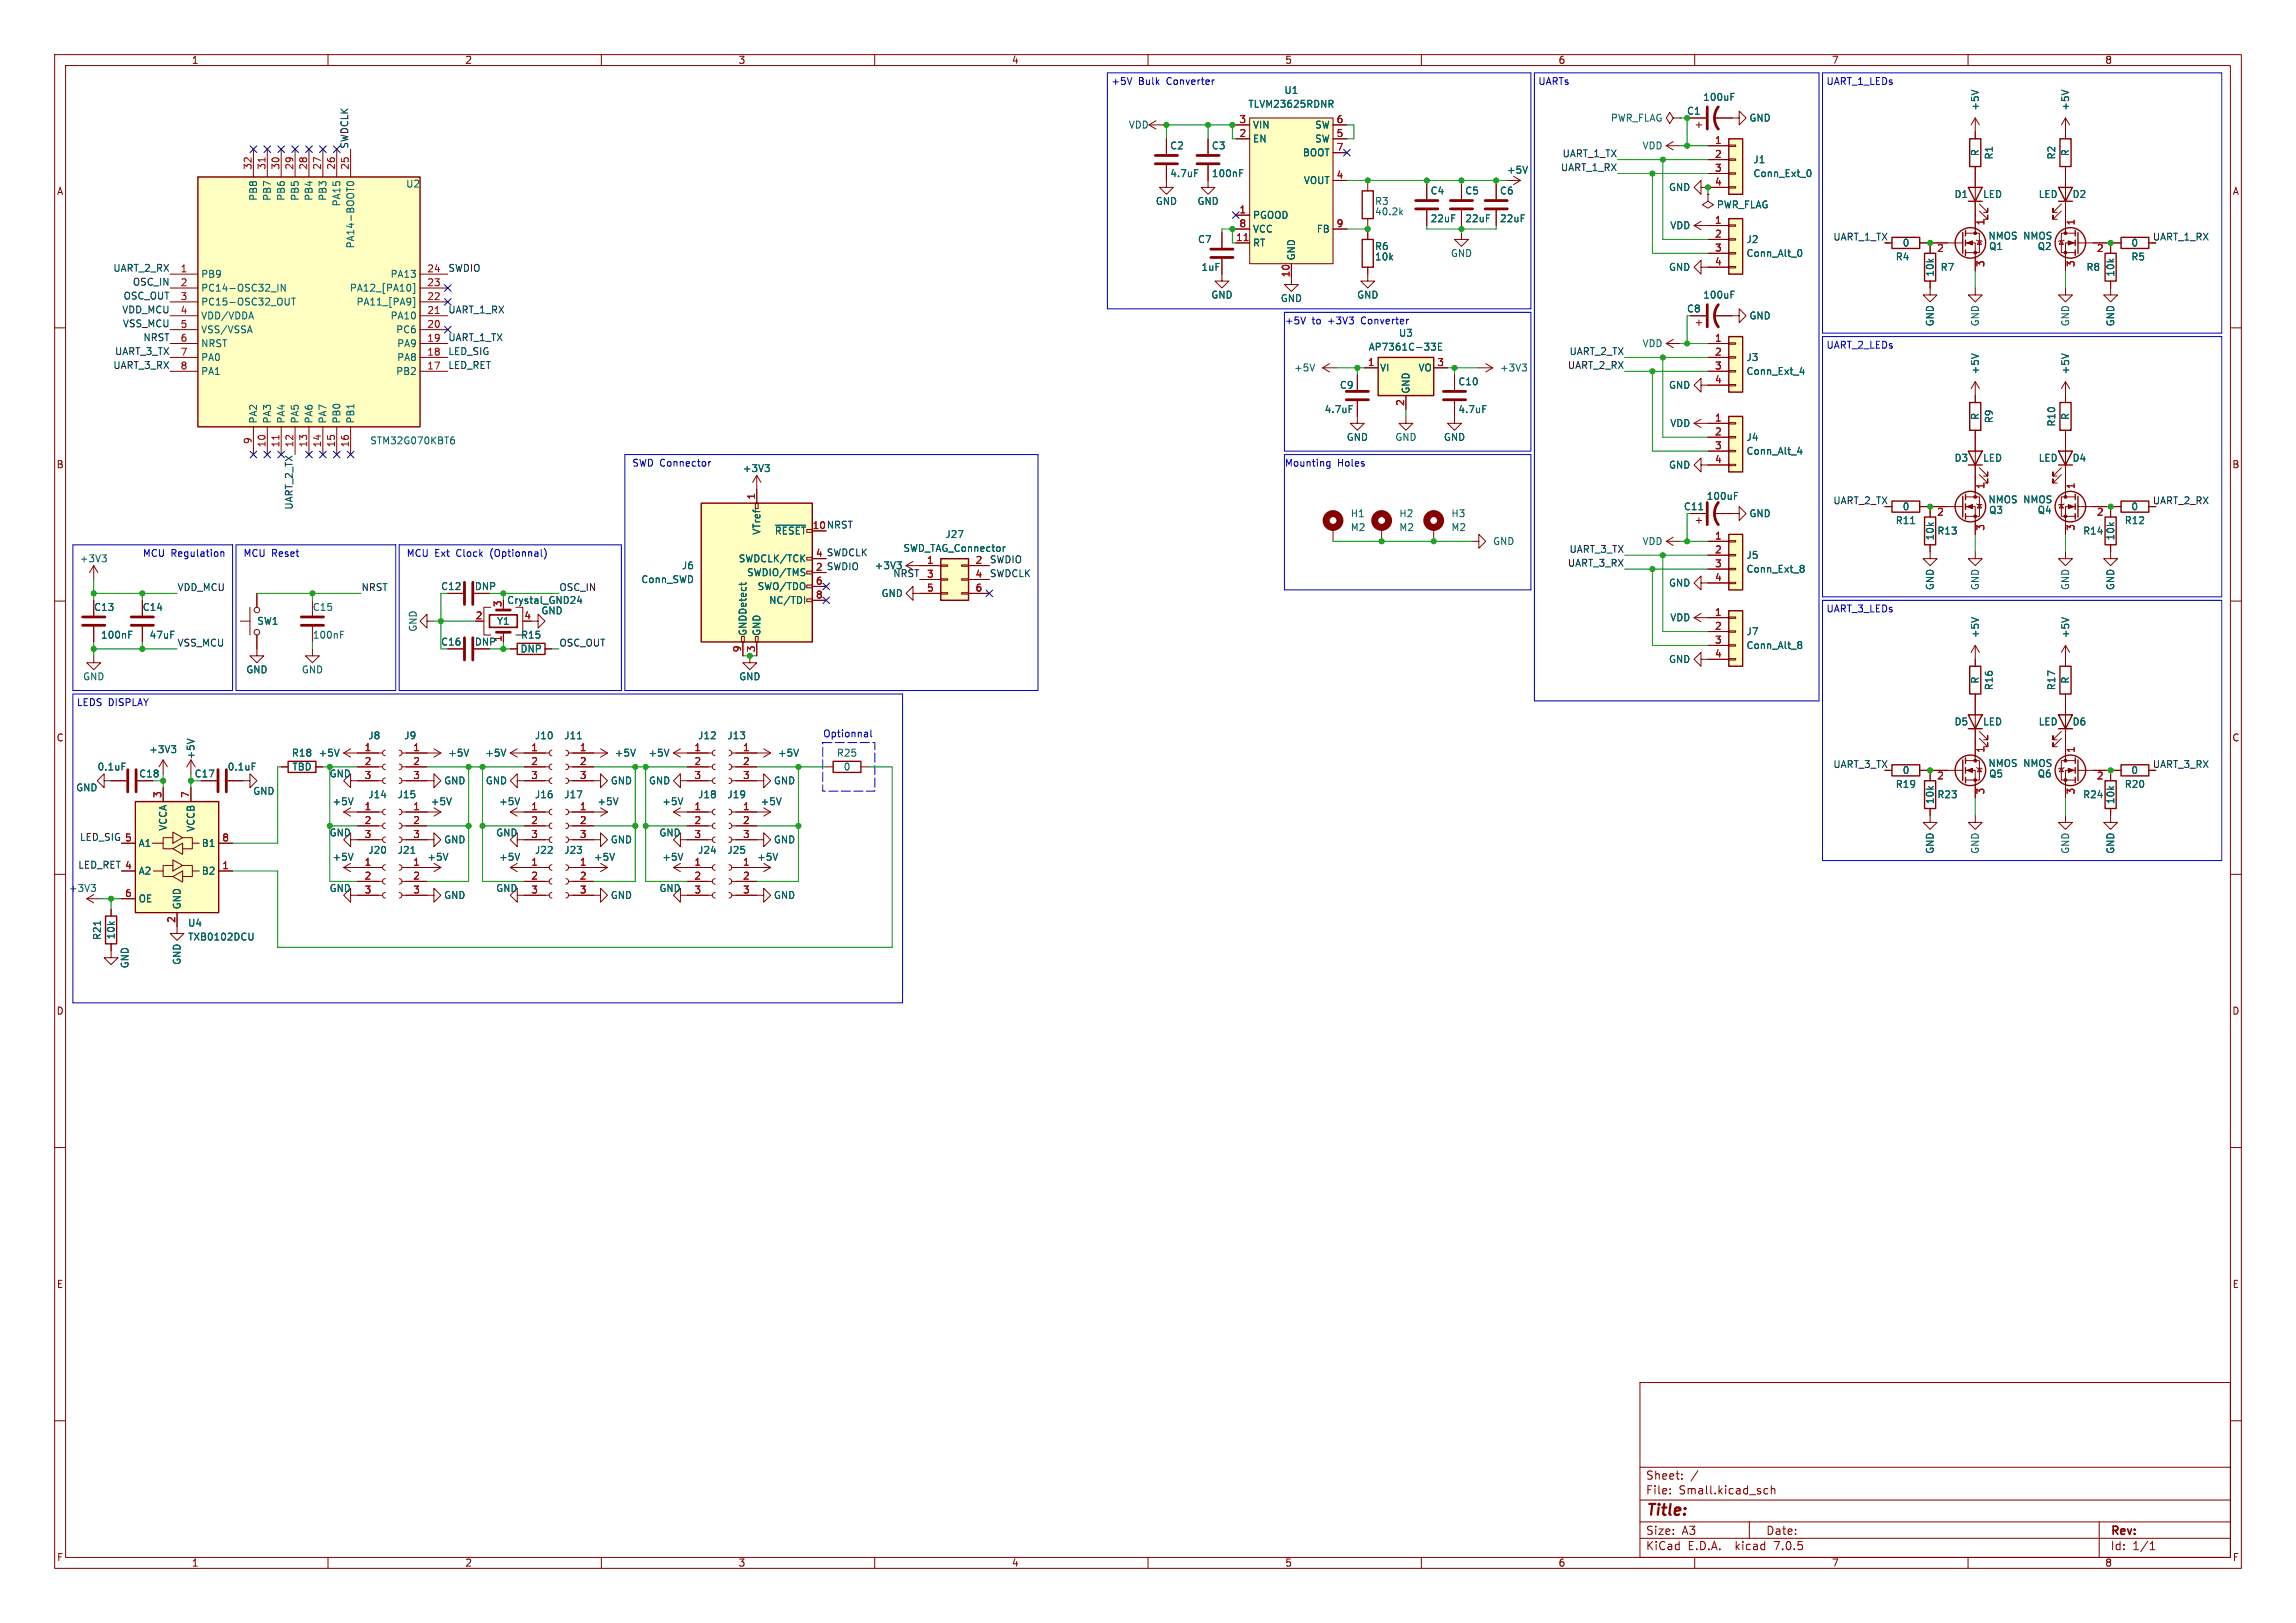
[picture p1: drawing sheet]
<svg xmlns="http://www.w3.org/2000/svg" width="420mm" height="297mm" viewBox="0 0 420 297" stroke-linecap="round" stroke-linejoin="round" font-family="sans-serif">
<defs><g id="words">
<text font-size="2.8" fill="#840000" x="301" y="277.8">Title:</text>
<g font-size="2.1" fill="#840000">
<text x="301" y="273.6">File:</text>
<text x="301" y="270.9">Sheet:</text>
<text x="307" y="273.6">Small.kicad_sch</text>
<text x="301" y="281">Size:</text>
<text x="307.6" y="281">A3</text>
<text x="323" y="281">Date:</text>
<text x="386" y="281.2">Rev:</text>
<text x="301" y="283.8">KiCad</text>
<text x="308.6" y="283.8">E.D.A.</text>
<text x="317.4" y="283.8">kicad</text>
<text x="324.5" y="283.8">7.0.5</text>
<text x="386" y="283.8">Id:</text>
<text x="390" y="283.8">1/1</text>
</g>
<g font-size="1.8" fill="#840000">
<text x="35" y="11.8">1</text>
<text x="85" y="11.8">2</text>
<text x="135" y="11.8">3</text>
<text x="185" y="11.8">4</text>
<text x="235" y="11.8">5</text>
<text x="285" y="11.8">6</text>
<text x="335" y="11.8">7</text>
<text x="385" y="11.8">8</text>
<text x="10.4" y="35.8">A</text>
<text x="408.4" y="35.8">A</text>
<text x="10.3" y="85.8">B</text>
<text x="408.3" y="85.8">B</text>
<text x="148.6" y="96.9">10 NRST</text>
<text x="86.8" y="108.1">DNP</text>
<text x="86.8" y="118.3">DNP</text>
<text x="10.3" y="135.8">C</text>
<text x="408.3" y="135.8">C</text>
<text x="25.4" y="142.4">C18</text>
<text x="10.3" y="185.8">D</text>
<text x="408.3" y="185.8">D</text>
<text x="10.4" y="235.8">E</text>
<text x="408.3" y="235.8">E</text>
<text x="10.4" y="285.8">F</text>
<text x="35" y="286.8">1</text>
<text x="85" y="286.8">2</text>
<text x="135" y="286.8">3</text>
<text x="185" y="286.8">4</text>
<text x="235" y="286.8">5</text>
<text x="285" y="286.8">6</text>
<text x="335" y="286.8">7</text>
<text x="385" y="286.8">8</text>
<text x="408.4" y="285.8">F</text>
</g>
<g font-size="1.8" fill="#0000c2">
<text x="203.2" y="15.6">+5V</text>
<text x="208.2" y="15.6">Bulk</text>
<text x="213.4" y="15.6">Converter</text>
<text x="281.3" y="15.6">UARTs</text>
<text x="334" y="15.6">UART_1_LEDs</text>
<text x="234.9" y="59.4">+5V</text>
<text x="239.9" y="59.4">to</text>
<text x="242.9" y="59.4">+3V3</text>
<text x="249.1" y="59.4">Converter</text>
<text x="334" y="63.9">UART_2_LEDs</text>
<text x="115.6" y="85.5">SWD Connector</text>
<text x="234.9" y="85.5">Mounting</text>
<text x="244.6" y="85.5">Holes</text>
<text x="26" y="102">MCU Regulation</text>
<text x="44.4" y="102">MCU Reset</text>
<text x="74.3" y="102">MCU Ext</text>
<text x="83.4" y="102">Clock</text>
<text x="89.7" y="102">(Optionnal)</text>
<text x="334" y="112.1">UART_3_LEDs</text>
<text x="14" y="129.3">LEDS DISPLAY</text>
<text x="150.5" y="135">Optionnal</text>
</g>
<g font-size="1.8" fill="#006464">
<text x="234.9" y="17.3">U1</text>
<text x="206.4" y="23.7">VDD</text>
<text x="228.3" y="19.9">TLVM23625RDNR</text>
<text x="229.1" y="23.7">VIN</text>
<text x="240.5" y="23.7">SW</text>
<text x="294.6" y="22.4">PWR_FLAG</text>
<text x="308.5" y="21.1">C1</text>
<text x="311.5" y="18.6">100uF</text>
<text x="319.9" y="22.4">GND</text>
<text x="362.1" y="20.3" transform="rotate(-90 362.1 20.3)">+5V</text>
<text x="378.7" y="20.3" transform="rotate(-90 378.7 20.3)">+5V</text>
<text x="214" y="27.5">C2</text>
<text x="221.6" y="27.5">C3</text>
<text x="229.1" y="26.2">EN</text>
<text x="238.3" y="28.8">BOOT</text>
<text x="240.5" y="26.2">SW</text>
<text x="300.4" y="27.5">VDD</text>
<text x="362.1" y="28.6" transform="rotate(-90 362.1 28.6)">R</text>
<text x="364.7" y="29.2" transform="rotate(-90 364.7 29.2)">R1</text>
<text x="376.1" y="29.2" transform="rotate(-90 376.1 29.2)">R2</text>
<text x="378.7" y="28.6" transform="rotate(-90 378.7 28.6)">R</text>
<text x="74.2" y="34.5">U2</text>
<text x="214" y="32.6">4.7uF</text>
<text x="221.6" y="32.6">100nF</text>
<text x="238.5" y="33.8">VOUT</text>
<text x="261.6" y="35.8">C4</text>
<text x="268" y="35.8">C5</text>
<text x="274.3" y="35.8">C6</text>
<text x="275.6" y="31.9">+5V</text>
<text x="305.2" y="35.1">GND</text>
<text x="320.7" y="30">J1</text>
<text x="320.7" y="32.6">Conn_Ext_0</text>
<text x="47.2" y="36.8" transform="rotate(-90 47.2 36.8)">PB8</text>
<text x="49.7" y="36.8" transform="rotate(-90 49.7 36.8)">PB7</text>
<text x="52.3" y="36.8" transform="rotate(-90 52.3 36.8)">PB6</text>
<text x="54.8" y="36.8" transform="rotate(-90 54.8 36.8)">PB5</text>
<text x="57.3" y="36.8" transform="rotate(-90 57.3 36.8)">PB4</text>
<text x="59.9" y="36.8" transform="rotate(-90 59.9 36.8)">PB3</text>
<text x="62.4" y="37.8" transform="rotate(-90 62.4 37.8)">PA15</text>
<text x="211.4" y="37.7">GND</text>
<text x="219" y="37.7">GND</text>
<text x="229.1" y="40.2">PGOOD</text>
<text x="251.5" y="37.7">R3</text>
<text x="251.5" y="39.6">40.2k</text>
<text x="261.6" y="40.8">22uF</text>
<text x="268" y="40.8">22uF</text>
<text x="274.3" y="40.8">22uF</text>
<text x="314" y="38.3">PWR_FLAG</text>
<text x="357.5" y="36.4">D1</text>
<text x="362.7" y="36.4">LED</text>
<text x="372.9" y="36.4">LED</text>
<text x="379.1" y="36.4">D2</text>
<text x="65" y="45.5" transform="rotate(-90 65 45.5)">PA14-BOOT0</text>
<text x="219.1" y="44.6">C7</text>
<text x="229.1" y="45.3">RT</text>
<text x="229.1" y="42.7">VCC</text>
<text x="237" y="47.8" transform="rotate(-90 237 47.8)">GND</text>
<text x="240.8" y="42.7">FB</text>
<text x="251.5" y="45.9">R6</text>
<text x="251.5" y="47.8">10k</text>
<text x="265.3" y="47.2">GND</text>
<text x="305.5" y="42.1">VDD</text>
<text x="319.4" y="44.6">J2</text>
<text x="319.4" y="47.2">Conn_Alt_0</text>
<text x="346.7" y="47.8">R4</text>
<text x="348" y="45.3">0</text>
<text x="363.7" y="44">NMOS NMOS</text>
<text x="363.8" y="45.9">Q1</text>
<text x="372.7" y="45.9">Q2</text>
<text x="389.8" y="47.8">R5</text>
<text x="389.8" y="45.3">0</text>
<text x="36.7" y="51">PB9</text>
<text x="36.7" y="53.5">PC14-OSC32_IN</text>
<text x="64" y="53.5">PA12_[PA10]</text>
<text x="71.4" y="51">PA13</text>
<text x="219.7" y="49.7">1uF</text>
<text x="305.2" y="49.7">GND</text>
<text x="353.9" y="50.7" transform="rotate(-90 353.9 50.7)">10k</text>
<text x="354.9" y="49.7">R7</text>
<text x="381.6" y="49.7">R8</text>
<text x="386.9" y="50.7" transform="rotate(-90 386.9 50.7)">10k</text>
<text x="36.7" y="56.1">PC15-OSC32_OUT</text>
<text x="36.7" y="58.6">VDD/VDDA</text>
<text x="65.2" y="56.1">PA11_[PA9]</text>
<text x="71.4" y="58.6">PA10</text>
<text x="221.5" y="54.8">GND</text>
<text x="234.2" y="55.4">GND</text>
<text x="248.2" y="54.8">GND</text>
<text x="308.5" y="57.3">C8</text>
<text x="311.5" y="54.8">100uF</text>
<text x="319.9" y="58.6">GND</text>
<text x="353.9" y="59.8" transform="rotate(-90 353.9 59.8)">GND</text>
<text x="362.1" y="59.8" transform="rotate(-90 362.1 59.8)">GND</text>
<text x="378.7" y="59.8" transform="rotate(-90 378.7 59.8)">GND</text>
<text x="386.9" y="59.8" transform="rotate(-90 386.9 59.8)">GND</text>
<text x="36.7" y="61.2">VSS/VSSA</text>
<text x="36.7" y="63.7">NRST</text>
<text x="72.5" y="61.2">PC6</text>
<text x="72.6" y="63.7">PA9</text>
<text x="250.3" y="64.3">AP7361C-33E</text>
<text x="255.8" y="61.8">U3</text>
<text x="300.4" y="63.7">VDD</text>
<text x="36.7" y="66.2">PA0</text>
<text x="36.7" y="68.8">PA1</text>
<text x="72.5" y="68.8">PB2</text>
<text x="72.6" y="66.2">PA8</text>
<text x="236.7" y="68.1">+5V</text>
<text x="245" y="71.3">C9</text>
<text x="252.3" y="68.1">VI</text>
<text x="259.5" y="68.1">VO</text>
<text x="266.7" y="70.7">C10</text>
<text x="274.3" y="68.1">+3V3</text>
<text x="305.2" y="71.3">GND</text>
<text x="319.4" y="66.2">J3</text>
<text x="319.4" y="68.8">Conn_Ext_4</text>
<text x="362.1" y="68.6" transform="rotate(-90 362.1 68.6)">+5V</text>
<text x="378.7" y="68.6" transform="rotate(-90 378.7 68.6)">+5V</text>
<text x="47.2" y="77.6" transform="rotate(-90 47.2 77.6)">PA2</text>
<text x="49.7" y="77.6" transform="rotate(-90 49.7 77.6)">PA3</text>
<text x="52.3" y="77.6" transform="rotate(-90 52.3 77.6)">PA4</text>
<text x="54.8" y="77.6" transform="rotate(-90 54.8 77.6)">PA5</text>
<text x="57.3" y="77.6" transform="rotate(-90 57.3 77.6)">PA6</text>
<text x="59.9" y="77.6" transform="rotate(-90 59.9 77.6)">PA7</text>
<text x="62.4" y="77.6" transform="rotate(-90 62.4 77.6)">PB0</text>
<text x="65" y="77.6" transform="rotate(-90 65 77.6)">PB1</text>
<text x="242.3" y="75.8">4.7uF</text>
<text x="258" y="72.1" transform="rotate(-90 258 72.1)">GND</text>
<text x="266.7" y="75.8">4.7uF</text>
<text x="362.1" y="76.9" transform="rotate(-90 362.1 76.9)">R</text>
<text x="364.7" y="77.5" transform="rotate(-90 364.7 77.5)">R9</text>
<text x="378.7" y="76.9" transform="rotate(-90 378.7 76.9)">R</text>
<text x="67.7" y="81.5">STM32G070KBT6</text>
<text x="246.3" y="80.8">GND</text>
<text x="255.2" y="80.8">GND</text>
<text x="264.1" y="80.8">GND</text>
<text x="305.5" y="78.3">VDD</text>
<text x="319.4" y="80.8">J4</text>
<text x="319.4" y="83.4">Conn_Alt_4</text>
<text x="376.1" y="78.1" transform="rotate(-90 376.1 78.1)">R10</text>
<text x="135.8" y="86.6">+3V3</text>
<text x="305.2" y="85.9">GND</text>
<text x="357.5" y="84.6">D3</text>
<text x="362.7" y="84.6">LED</text>
<text x="372.9" y="84.6">LED</text>
<text x="379.1" y="84.6">D4</text>
<text x="247" y="94.8">H1</text>
<text x="255.9" y="94.8">H2</text>
<text x="265.4" y="94.8">H3</text>
<text x="308" y="93.5">C11</text>
<text x="312.1" y="91.6">100uF</text>
<text x="319.9" y="94.8">GND</text>
<text x="348" y="93.5">0</text>
<text x="363.7" y="92.3">NMOS NMOS</text>
<text x="363.8" y="94.2">Q3</text>
<text x="372.7" y="94.2">Q4</text>
<text x="389.8" y="93.5">0</text>
<text x="139.3" y="97.9" transform="rotate(-90 139.3 97.9)">VTref</text>
<text x="141.7" y="98">~{RESET}</text>
<text x="165.2" y="101.2">SWD_TAG_Connector</text>
<text x="172.9" y="98.6">J27</text>
<text x="247" y="97.3">M2</text>
<text x="255.9" y="97.3">M2</text>
<text x="265.4" y="97.3">M2</text>
<text x="273.1" y="99.9">GND</text>
<text x="300.4" y="99.9">VDD</text>
<text x="346.7" y="96.1">R11</text>
<text x="353.9" y="98.9" transform="rotate(-90 353.9 98.9)">10k</text>
<text x="354.3" y="98">R13</text>
<text x="381" y="98">R14</text>
<text x="386.9" y="98.9" transform="rotate(-90 386.9 98.9)">10k</text>
<text x="388.6" y="96.1">R12</text>
<text x="14.5" y="103.1">+3V3</text>
<text x="117.2" y="106.9">Conn_SWD</text>
<text x="124.7" y="104.3">J6</text>
<text x="135.1" y="103.1">SWDCLK/TCK</text>
<text x="136.6" y="105.6">SWDIO/TMS</text>
<text x="160" y="104.3">+3V3</text>
<text x="163.4" y="105.7">NRST</text>
<text x="305.2" y="107.5">GND</text>
<text x="319.4" y="102.4">J5</text>
<text x="319.4" y="105">Conn_Ext_8</text>
<text x="17.2" y="112">C13</text>
<text x="26" y="112">C14</text>
<text x="57.2" y="112">C15</text>
<text x="80.6" y="108.1">C12</text>
<text x="92.7" y="110.7">Crystal_GND24</text>
<text x="99" y="112.6">GND</text>
<text x="138.6" y="108.1">SWO/TDO</text>
<text x="140.7" y="110.7">NC/TDI</text>
<text x="161.2" y="109.4">GND</text>
<text x="305.5" y="113.9">VDD</text>
<text x="353.9" y="108" transform="rotate(-90 353.9 108)">GND</text>
<text x="362.1" y="108" transform="rotate(-90 362.1 108)">GND</text>
<text x="378.7" y="108" transform="rotate(-90 378.7 108)">GND</text>
<text x="386.9" y="108" transform="rotate(-90 386.9 108)">GND</text>
<text x="18.4" y="117">100nF</text>
<text x="27.3" y="117">47uF</text>
<text x="47" y="114.5">SW1</text>
<text x="57.2" y="117">100nF</text>
<text x="76.4" y="115.7" transform="rotate(-90 76.4 115.7)">GND</text>
<text x="80.6" y="118.3">C16</text>
<text x="90.9" y="114.5">Y1</text>
<text x="91.8" y="117.5" transform="rotate(-90 91.8 117.5)">1</text>
<text x="95.2" y="119.6">DNP</text>
<text x="95.2" y="117">R15</text>
<text x="136.7" y="116.5" transform="rotate(-90 136.7 116.5)">GNDDetect</text>
<text x="139.3" y="116.5" transform="rotate(-90 139.3 116.5)">GND</text>
<text x="319.4" y="116.4">J7</text>
<text x="319.4" y="118.9">Conn_Alt_8</text>
<text x="362.1" y="116.8" transform="rotate(-90 362.1 116.8)">+5V</text>
<text x="378.7" y="116.8" transform="rotate(-90 378.7 116.8)">+5V</text>
<text x="15.1" y="124.7">GND</text>
<text x="45" y="123.4">GND</text>
<text x="55.2" y="123.4">GND</text>
<text x="135.2" y="124.7">GND</text>
<text x="305.2" y="121.5">GND</text>
<text x="362.1" y="125.2" transform="rotate(-90 362.1 125.2)">R</text>
<text x="378.7" y="125.2" transform="rotate(-90 378.7 125.2)">R</text>
<text x="364.7" y="126.4" transform="rotate(-90 364.7 126.4)">R16</text>
<text x="376.1" y="126.4" transform="rotate(-90 376.1 126.4)">R17</text>
<text x="27.2" y="138">+3V3</text>
<text x="67.3" y="135.4">J8</text>
<text x="73.9" y="135.4">J9</text>
<text x="97.8" y="135.4">J10</text>
<text x="103.2" y="135.4">J11</text>
<text x="127.6" y="135.4">J12</text>
<text x="133" y="135.4">J13</text>
<text x="357.5" y="132.9">D5</text>
<text x="362.7" y="132.9">LED</text>
<text x="372.9" y="132.9">LED</text>
<text x="379.1" y="132.9">D6</text>
<text x="17.8" y="141.2">0.1uF</text>
<text x="35.5" y="142.4">C17</text>
<text x="35.8" y="139.1" transform="rotate(-90 35.8 139.1)">+5V</text>
<text x="41.6" y="141.2">0.1uF</text>
<text x="53.3" y="138.6">R18</text>
<text x="53.4" y="141.2">TBD</text>
<text x="58.2" y="138.6">+5V</text>
<text x="60.2" y="142.4">GND</text>
<text x="81.2" y="143.7">GND</text>
<text x="81.9" y="138.6">+5V</text>
<text x="88.7" y="138.6">+5V</text>
<text x="88.8" y="143.7">GND</text>
<text x="111.7" y="143.7">GND</text>
<text x="112.4" y="138.6">+5V</text>
<text x="118.5" y="138.6">+5V</text>
<text x="118.7" y="143.7">GND</text>
<text x="141.5" y="143.7">GND</text>
<text x="142.2" y="138.6">+5V</text>
<text x="153" y="138.6">R25</text>
<text x="154.3" y="141.2">0</text>
<text x="348" y="141.8">0</text>
<text x="363.7" y="140.5">NMOS NMOS</text>
<text x="363.8" y="142.4">Q5</text>
<text x="372.7" y="142.4">Q6</text>
<text x="389.8" y="141.8">0</text>
<text x="13.9" y="145">GND</text>
<text x="46.3" y="145.6">GND</text>
<text x="60.8" y="147.5">+5V</text>
<text x="67.3" y="146.2">J14</text>
<text x="72.7" y="146.2">J15</text>
<text x="78.7" y="147.5">+5V</text>
<text x="91.2" y="147.5">+5V</text>
<text x="97.8" y="146.2">J16</text>
<text x="103.2" y="146.2">J17</text>
<text x="109.2" y="147.5">+5V</text>
<text x="121.1" y="147.5">+5V</text>
<text x="127.6" y="146.2">J18</text>
<text x="133" y="146.2">J19</text>
<text x="139.1" y="147.5">+5V</text>
<text x="346.7" y="144.3">R19</text>
<text x="353.9" y="147.2" transform="rotate(-90 353.9 147.2)">10k</text>
<text x="354.3" y="146.2">R23</text>
<text x="381" y="146.2">R24</text>
<text x="386.9" y="147.2" transform="rotate(-90 386.9 147.2)">10k</text>
<text x="388.6" y="144.3">R20</text>
<text x="25.3" y="155.1">A1</text>
<text x="30.7" y="152" transform="rotate(-90 30.7 152)">VCCA</text>
<text x="35.8" y="152.2" transform="rotate(-90 35.8 152.2)">VCCB</text>
<text x="36.9" y="155.1">B1</text>
<text x="60.2" y="153.2">GND</text>
<text x="81.2" y="154.5">GND</text>
<text x="90.7" y="153.2">GND</text>
<text x="111.7" y="154.5">GND</text>
<text x="120.6" y="153.2">GND</text>
<text x="141.5" y="154.5">GND</text>
<text x="25.3" y="160.2">A2</text>
<text x="36.9" y="160.2">B2</text>
<text x="60.8" y="157.7">+5V</text>
<text x="67.3" y="156.4">J20</text>
<text x="72.7" y="156.4">J21</text>
<text x="78.1" y="157.7">+5V</text>
<text x="91.2" y="157.7">+5V</text>
<text x="97.8" y="156.4">J22</text>
<text x="103.2" y="156.4">J23</text>
<text x="108.6" y="157.7">+5V</text>
<text x="121.1" y="157.7">+5V</text>
<text x="127.6" y="156.4">J24</text>
<text x="133" y="156.4">J25</text>
<text x="138.4" y="157.7">+5V</text>
<text x="353.9" y="156.3" transform="rotate(-90 353.9 156.3)">GND</text>
<text x="362.1" y="156.3" transform="rotate(-90 362.1 156.3)">GND</text>
<text x="378.7" y="156.3" transform="rotate(-90 378.7 156.3)">GND</text>
<text x="386.9" y="156.3" transform="rotate(-90 386.9 156.3)">GND</text>
<text x="12.6" y="163.4">+3V3</text>
<text x="25.3" y="165.3">OE</text>
<text x="33.2" y="166.5" transform="rotate(-90 33.2 166.5)">GND</text>
<text x="60.2" y="163.4">GND</text>
<text x="81.2" y="164.7">GND</text>
<text x="90.7" y="163.4">GND</text>
<text x="111.7" y="164.7">GND</text>
<text x="120.6" y="163.4">GND</text>
<text x="141.5" y="164.7">GND</text>
<text x="18.6" y="172.1" transform="rotate(-90 18.6 172.1)">R21</text>
<text x="21.1" y="172" transform="rotate(-90 21.1 172)">10k</text>
<text x="34.3" y="169.7">U4</text>
<text x="34.3" y="172.3">TXB0102DCU</text>
<text x="23.7" y="177.3" transform="rotate(-90 23.7 177.3)">GND</text>
<text x="33.2" y="176.6" transform="rotate(-90 33.2 176.6)">GND</text>
</g>
<g font-size="1.8" fill="#a90000">
<text x="226.7" y="22.6">3</text>
<text x="244.4" y="22.6">6</text>
<text x="226.7" y="25.1">2</text>
<text x="244.4" y="25.1">5</text>
<text x="244.4" y="27.7">7</text>
<text x="313.7" y="26.4">1</text>
<text x="313.7" y="29">2</text>
<text x="46.1" y="31.1" transform="rotate(-90 46.1 31.1)">32</text>
<text x="48.6" y="31.1" transform="rotate(-90 48.6 31.1)">31</text>
<text x="51.2" y="31.1" transform="rotate(-90 51.2 31.1)">30</text>
<text x="53.7" y="31.1" transform="rotate(-90 53.7 31.1)">29</text>
<text x="56.3" y="31.1" transform="rotate(-90 56.3 31.1)">28</text>
<text x="58.8" y="31.1" transform="rotate(-90 58.8 31.1)">27</text>
<text x="61.3" y="31.1" transform="rotate(-90 61.3 31.1)">26</text>
<text x="63.9" y="31.1" transform="rotate(-90 63.9 31.1)">25</text>
<text x="244.4" y="32.8">4</text>
<text x="313.7" y="31.5">3</text>
<text x="313.7" y="34">4</text>
<text x="226.7" y="39.1">1</text>
<text x="226.7" y="41.7">8</text>
<text x="244.4" y="41.7">9</text>
<text x="313.7" y="41">1</text>
<text x="363.2" y="41.3" transform="rotate(-90 363.2 41.3)">1</text>
<text x="379.7" y="41.3" transform="rotate(-90 379.7 41.3)">1</text>
<text x="226.1" y="44.2">11</text>
<text x="313.7" y="43.6">2</text>
<text x="313.7" y="46.1">3</text>
<text x="354.3" y="46.4">2</text>
<text x="383.5" y="46.4">2</text>
<text x="33" y="49.9">1</text>
<text x="33" y="52.5">2</text>
<text x="78.1" y="52.5">23</text>
<text x="78.1" y="49.9">24</text>
<text x="236" y="50.8" transform="rotate(-90 236 50.8)">10</text>
<text x="313.7" y="48.6">4</text>
<text x="363.2" y="48.9" transform="rotate(-90 363.2 48.9)">3</text>
<text x="379.7" y="48.9" transform="rotate(-90 379.7 48.9)">3</text>
<text x="33" y="55">3</text>
<text x="33" y="57.5">4</text>
<text x="78.1" y="57.5">21</text>
<text x="78.1" y="55">22</text>
<text x="33" y="60.1">5</text>
<text x="33" y="62.6">6</text>
<text x="33" y="65.2">7</text>
<text x="78.1" y="65.2">18</text>
<text x="78.1" y="62.6">19</text>
<text x="78.1" y="60.1">20</text>
<text x="313.7" y="62.6">1</text>
<text x="313.7" y="65.2">2</text>
<text x="33" y="67.7">8</text>
<text x="78.1" y="67.7">17</text>
<text x="250.2" y="67.1">1</text>
<text x="262.9" y="67.1">3</text>
<text x="313.7" y="67.7">3</text>
<text x="313.7" y="70.2">4</text>
<text x="256.9" y="74.3" transform="rotate(-90 256.9 74.3)">2</text>
<text x="313.7" y="77.2">1</text>
<text x="46.1" y="81.3" transform="rotate(-90 46.1 81.3)">9</text>
<text x="48.6" y="81.9" transform="rotate(-90 48.6 81.9)">10</text>
<text x="51.2" y="81.9" transform="rotate(-90 51.2 81.9)">11</text>
<text x="53.7" y="81.9" transform="rotate(-90 53.7 81.9)">12</text>
<text x="56.3" y="81.9" transform="rotate(-90 56.3 81.9)">13</text>
<text x="58.8" y="81.9" transform="rotate(-90 58.8 81.9)">14</text>
<text x="61.3" y="81.9" transform="rotate(-90 61.3 81.9)">15</text>
<text x="63.9" y="81.9" transform="rotate(-90 63.9 81.9)">16</text>
<text x="313.7" y="79.8">2</text>
<text x="313.7" y="82.3">3</text>
<text x="313.7" y="84.8">4</text>
<text x="363.2" y="89.6" transform="rotate(-90 363.2 89.6)">1</text>
<text x="379.7" y="89.6" transform="rotate(-90 379.7 89.6)">1</text>
<text x="138.2" y="91.5" transform="rotate(-90 138.2 91.5)">1</text>
<text x="354.3" y="94.6">2</text>
<text x="383.5" y="94.6">2</text>
<text x="148.6" y="96.9">10</text>
<text x="149.2" y="102">4</text>
<text x="313.7" y="98.8">1</text>
<text x="313.7" y="101.3">2</text>
<text x="363.2" y="97.2" transform="rotate(-90 363.2 97.2)">3</text>
<text x="379.7" y="97.2" transform="rotate(-90 379.7 97.2)">3</text>
<text x="149.2" y="107.1">6</text>
<text x="149.2" y="104.5">2</text>
<text x="169.5" y="103.3">1</text>
<text x="169.5" y="105.8">3</text>
<text x="178.4" y="103.3">2</text>
<text x="178.4" y="105.8">4</text>
<text x="313.7" y="103.9">3</text>
<text x="313.7" y="106.4">4</text>
<text x="87" y="113.4">2</text>
<text x="91.8" y="111.2" transform="rotate(-90 91.8 111.2)">3</text>
<text x="95.9" y="113.4">4</text>
<text x="149.2" y="109.6">8</text>
<text x="169.5" y="108.3">5</text>
<text x="178.4" y="108.3">6</text>
<text x="313.7" y="112.8">1</text>
<text x="135.6" y="119.4" transform="rotate(-90 135.6 119.4)">9</text>
<text x="138.2" y="119.4" transform="rotate(-90 138.2 119.4)">3</text>
<text x="313.7" y="115.3">2</text>
<text x="313.7" y="117.9">3</text>
<text x="313.7" y="120.4">4</text>
<text x="66.6" y="137.5">1</text>
<text x="75.5" y="137.5">1</text>
<text x="97.1" y="137.5">1</text>
<text x="106" y="137.5">1</text>
<text x="127" y="137.5">1</text>
<text x="135.9" y="137.5">1</text>
<text x="363.2" y="137.8" transform="rotate(-90 363.2 137.8)">1</text>
<text x="379.7" y="137.8" transform="rotate(-90 379.7 137.8)">1</text>
<text x="66.6" y="140.1">2</text>
<text x="66.6" y="142.6">3</text>
<text x="75.5" y="140.1">2</text>
<text x="75.5" y="142.6">3</text>
<text x="97.1" y="140.1">2</text>
<text x="97.1" y="142.6">3</text>
<text x="106" y="140.1">2</text>
<text x="106" y="142.6">3</text>
<text x="127" y="140.1">2</text>
<text x="127" y="142.6">3</text>
<text x="135.9" y="140.1">2</text>
<text x="135.9" y="142.6">3</text>
<text x="354.3" y="142.9">2</text>
<text x="383.5" y="142.9">2</text>
<text x="29.6" y="146.1" transform="rotate(-90 29.6 146.1)">3</text>
<text x="34.7" y="146.1" transform="rotate(-90 34.7 146.1)">7</text>
<text x="66.6" y="148.3">1</text>
<text x="75.5" y="148.3">1</text>
<text x="97.1" y="148.3">1</text>
<text x="106" y="148.3">1</text>
<text x="127" y="148.3">1</text>
<text x="135.9" y="148.3">1</text>
<text x="363.2" y="145.4" transform="rotate(-90 363.2 145.4)">3</text>
<text x="379.7" y="145.4" transform="rotate(-90 379.7 145.4)">3</text>
<text x="22.8" y="154.1">5</text>
<text x="40.6" y="154.1">8</text>
<text x="66.6" y="150.9">2</text>
<text x="66.6" y="153.4">3</text>
<text x="75.5" y="150.9">2</text>
<text x="75.5" y="153.4">3</text>
<text x="97.1" y="150.9">2</text>
<text x="97.1" y="153.4">3</text>
<text x="106" y="150.9">2</text>
<text x="106" y="153.4">3</text>
<text x="127" y="150.9">2</text>
<text x="127" y="153.4">3</text>
<text x="135.9" y="150.9">2</text>
<text x="135.9" y="153.4">3</text>
<text x="22.8" y="159.1">4</text>
<text x="40.6" y="159.1">1</text>
<text x="66.6" y="158.5">1</text>
<text x="66.6" y="161">2</text>
<text x="75.5" y="158.5">1</text>
<text x="75.5" y="161">2</text>
<text x="97.1" y="158.5">1</text>
<text x="97.1" y="161">2</text>
<text x="106" y="158.5">1</text>
<text x="106" y="161">2</text>
<text x="127" y="158.5">1</text>
<text x="127" y="161">2</text>
<text x="135.9" y="158.5">1</text>
<text x="135.9" y="161">2</text>
<text x="22.8" y="164.2">6</text>
<text x="66.6" y="163.6">3</text>
<text x="75.5" y="163.6">3</text>
<text x="97.1" y="163.6">3</text>
<text x="106" y="163.6">3</text>
<text x="127" y="163.6">3</text>
<text x="135.9" y="163.6">3</text>
<text x="32.1" y="168.9" transform="rotate(-90 32.1 168.9)">2</text>
</g>
<g font-size="1.8" fill="#0f0f0f">
<text x="63.8" y="27.3" transform="rotate(-90 63.8 27.3)">SWDCLK</text>
<text x="285.8" y="28.9">UART_1_TX</text>
<text x="285.5" y="31.4">UART_1_RX</text>
<text x="20.7" y="49.8">UART_2_RX</text>
<text x="24.3" y="52.4">OSC_IN</text>
<text x="81.9" y="49.8">SWDIO</text>
<text x="22.3" y="57.4">VDD_MCU</text>
<text x="22.5" y="60">VSS_MCU</text>
<text x="22.6" y="54.9">OSC_OUT</text>
<text x="81.9" y="57.4">UART_1_RX</text>
<text x="21" y="65.1">UART_3_TX</text>
<text x="26.2" y="62.5">NRST</text>
<text x="81.9" y="65.1">LED_SIG</text>
<text x="81.9" y="62.5">UART_1_TX</text>
<text x="287.1" y="65.1">UART_2_TX</text>
<text x="20.7" y="67.6">UART_3_RX</text>
<text x="81.9" y="67.6">LED_RET</text>
<text x="286.8" y="67.6">UART_2_RX</text>
<text x="53.6" y="93.3" transform="rotate(-90 53.6 93.3)">UART_2_TX</text>
<text x="149.2" y="102">4 SWDCLK</text>
<text x="287.1" y="101.3">UART_3_TX</text>
<text x="149.2" y="104.5">2 SWDIO</text>
<text x="181" y="103.2">SWDIO</text>
<text x="181" y="105.7">SWDCLK</text>
<text x="286.8" y="103.8">UART_3_RX</text>
<text x="32.4" y="108.2">VDD_MCU</text>
<text x="66" y="108.2">NRST</text>
<text x="102.2" y="108.2">OSC_IN</text>
<text x="32.4" y="118.4">VSS_MCU</text>
<text x="102.2" y="118.4">OSC_OUT</text>
<text x="14.6" y="154">LED_SIG 5</text>
<text x="14.3" y="159">LED_RET 4</text>
</g>
<g font-size="1.8" fill="#009600">
<text x="335.3" y="44.1">UART_1_TX</text>
<text x="393.7" y="44.1">UART_1_RX</text>
<text x="335.3" y="92.4">UART_2_TX</text>
<text x="393.7" y="92.4">UART_2_RX</text>
<text x="335.3" y="140.6">UART_3_TX</text>
<text x="393.7" y="140.6">UART_3_RX</text>
</g>
</g></defs>
<g fill="none" stroke="#840000" stroke-width=".18">
<path d="M10 10h400v277h-400zM12 12h396v273h-396zM60 10v2M110 10v2M160 10v2M210 10v2M260 10v2M310 10v2M360 10v2M46.4 27.3v5.1M48.9 27.3v5.1M51.4 27.3v5.1"/>
<path d="M54 27.3v5.1M56.5 27.3v5.1M59.1 27.3v5.1M61.6 27.3v5.1M64.1 27.3v5.1M210.2 22.9h2.5M210.2 22.9l1.3 .7M211.5 22.1l-1.3 .8M213.4 30.2v4.1h1.2l-1.2 1.3-1.3-1.3h1.3M213.4 25.4v2.8M221 30.2v4.1h1.2l-1.2 1.3-1.3-1.3h1.3M221 25.4v2.8"/>
<path d="M226.1 22.9h2.5M226.1 39.4h2.5M226.1 25.4h2.5M228.6 21.6h15.2v26.7h-15.2zM243.8 22.9h2.6M243.8 25.4h2.6M243.8 33h2.6M243.8 27.9h2.6M250.2 33.7v1.2M261 33.7v2.7M261 38.5v2.8M267.3 33.7v2.7"/>
<path d="M267.3 38.5v2.8M273.7 33.7v2.7M273.7 38.5v2.8M275.6 33h2.5M276.9 32.3l1.2 .7M278.1 33l-1.2 .8M304.8 26.7h2.5M304.8 26.7l1.3 .7M306.1 21.6l-.7-1-.6 1 .6 1 .7-1h1.2M306.1 25.9l-1.3 .8M307.3 21.6h.1M309.2 21.6h2.8"/>
<path d="M310.3 22.9h1M310.8 22.4v1M311.1 34.3v-1.3l-1.2 1.3 1.2 1.3v-1.3h5.1M312.4 35.6v1.2l1 .7-1 .6-1-.6 1-.7M312.4 35.6h.1M312.4 26.7h3.8M312.4 29.2h3.8M312.4 31.8h3.8M313.6 21.6h4.5v-1.3l1.3 1.3-1.3 1.3v-1.3M316.2 34.2h1.3v.2h-1.3zM316.2 31.6h1.3v.3h-1.3zM316.2 29.1h1.3v.2h-1.3z"/>
<path d="M316.2 26.5h1.3v.3h-1.3zM361.3 21.6v3.8M361.3 30.5v12.2M361.3 21.6l-.7 1.3M361.3 21.6l.8 1.3M362.1 38.6l1.5 1.5v-.7v.7h-.8M362.1 37.3l1.5 1.6v-.8v.8h-.8M377.1 38.6l-1.6 1.5v-.7v.7h.8M377.1 37.3l-1.6 1.6v-.8v.8h.8M377.8 21.6v3.8M377.8 30.5v12.2M377.8 21.6l.8 1.3"/>
<path d="M377.8 21.6l-.7 1.3M10 60h2M31.1 57.8h5.1M31.1 50.2h5.1M31.1 52.7h5.1M31.1 55.2h5.1M76.8 57.8h5.1M76.8 50.2h5.1M76.8 52.7h5.1M76.8 55.2h5.1M223.5 47.4v4h1.3l-1.3 1.3-1.3-1.3h1.3M223.5 42.5v2.8"/>
<path d="M226.1 44.5h2.5M226.1 41.9h2.5M236.2 48.3v3.8h1.3l-1.3 1.2-1.3-1.2h1.3M243.8 41.9h2.6M250.2 48.9v2.5h1.3l-1.3 1.3-1.3-1.3h1.3M250.2 40v1.3M250.2 42.5v1.3M267.3 42.5v1.3h1.3l-1.3 1.3-1.2-1.3h1.2M309.2 57.8h2.8M309.9 41.3h6.3M309.9 41.3l1.2 .7M310.3 59.1h1"/>
<path d="M310.8 58.5v1.1M311.1 48.9v-1.3l-1.2 1.3 1.2 1.3v-1.3h5.1M311.1 40.5l-1.2 .8M312.4 43.8h3.8M312.4 46.4h3.8M313.6 57.8h4.5v-1.3l1.3 1.3-1.3 1.3v-1.3M316.2 48.8h1.3v.2h-1.3zM316.2 46.2h1.3v.3h-1.3zM316.2 43.7h1.3v.2h-1.3zM316.2 41.1h1.3v.3h-1.3zM344.8 44.5h1.3M351.2 44.5h1.2"/>
<path d="M353.1 51.4v2.6h1.2l-1.2 1.2-1.3-1.2h1.3M353.1 45.1v1.3M353.7 44.5h5.3M359.5 44.5h1.8v5M359.5 42.7h2.6v3.5h-2.6M361.3 52.7v1.3h1.3l-1.3 1.2-1.3-1.2h1.3M361.6 43.9l.1 .2h.8l.1 .1M362.1 44.1l.4 .6h-.8zM377.1 44.1l.3 .6h-.7zM377.6 43.9l-.2 .2h-.7l-.1 .1M377.8 52.7v1.3h-1.2l1.2 1.2 1.3-1.2h-1.3M379.6 44.5h-1.8v5"/>
<path d="M379.6 42.7h-2.5v3.5h2.5M380.1 44.5h5.3M386.1 51.4v2.6h-1.3l1.3 1.2 1.2-1.2h-1.2M386.1 45.1v1.3M386.7 44.5h1.3M393.1 44.5h1.2M408 60h2M31.1 62.9h5.1M31.1 65.4h5.1M31.1 67.9h5.1M31.1 60.3h5.1M46.4 78.1v5.1"/>
<path d="M48.9 78.1v5.1M51.4 78.1v5.1M54 78.1v5.1M56.5 78.1v5.1M59.1 78.1v5.1M61.6 78.1v5.1M64.1 78.1v5.1M76.8 62.9h5.1M76.8 65.4h5.1M76.8 67.9h5.1M76.8 60.3h5.1M241.9 67.3h2.6"/>
<path d="M241.9 67.3l1.3 .8M243.2 66.5l-1.3 .8M248.3 73.4v4.1h-1.3l1.3 1.2 1.3-1.2h-1.3M248.3 68.6v2.8M249.6 67.3h2.5M257.2 76.2v1.3h1.2l-1.2 1.2-1.3-1.2h1.3M257.2 72.4v2.5M262.3 67.3h2.5M266.1 73.4v4.1h1.2l-1.2 1.2-1.3-1.2h1.3M266.1 68.6v2.8M270.5 67.3h2.5M271.8 66.5l1.2 .8"/>
<path d="M273 67.3l-1.2 .8M304.8 62.9h2.5M304.8 62.9l1.3 .7M306.1 62.1l-1.3 .8M309.9 77.5h6.3M309.9 77.5l1.2 .7M311.1 70.5v-1.3l-1.2 1.3 1.2 1.3v-1.3h5.1M311.1 76.7l-1.2 .8M312.4 62.9h3.8M312.4 65.4h3.8M312.4 67.9h3.8M316.2 70.4h1.3v.2h-1.3z"/>
<path d="M316.2 67.8h1.3v.3h-1.3zM316.2 65.3h1.3v.2h-1.3zM316.2 62.7h1.3v.3h-1.3zM316.2 79.9h1.3v.2h-1.3zM316.2 77.3h1.3v.3h-1.3zM361.3 69.9v3.8M361.3 78.7v12.2M361.3 69.9l-.7 1.2M361.3 69.9l.8 1.2M377.8 69.9v3.8M377.8 78.7v12.2M377.8 69.9l.8 1.2"/>
<path d="M377.8 69.9l-.7 1.2M138.2 92.1h.5v1h-.5zM138.4 87l-.7 1.3M138.4 87v5.1M138.4 87l.8 1.3M243.8 96.5v2.6M252.7 96.5v2.6M262.3 96.5v2.6M269.2 99.1h1.3v-1.3l1.3 1.3-1.3 1.2v-1.2M304.8 99.1h2.5M304.8 99.1l1.3 .7M306.1 98.3l-1.3 .8"/>
<path d="M309.2 94h2.8M310.3 95.3h1M310.8 94.7v1.1M311.1 85.1v-1.3l-1.2 1.3 1.2 1.3v-1.3h5.1M312.4 99.1h3.8M312.4 80h3.8M312.4 82.6h3.8M313.6 94h4.5v-1.3l1.3 1.3-1.3 1.3v-1.3M316.2 98.9h1.3v.3h-1.3zM316.2 85h1.3v.2h-1.3zM316.2 82.4h1.3v.3h-1.3zM344.8 92.7h1.3"/>
<path d="M351.2 92.7h1.2M353.1 99.7v2.5h1.2l-1.2 1.3-1.3-1.3h1.3M353.1 93.3v1.3M353.7 92.7h5.3M359.5 92.7h1.8v5.1M359.5 90.9h2.6v3.6h-2.6M361.6 92.2l.1 .1h.8l.1 .2M362.1 86.9l1.5 1.5v-.8v.8h-.8M362.1 85.6l1.5 1.5v-.7v.7h-.8M362.1 92.3l.4 .7h-.8zM377.1 86.9l-1.6 1.5v-.8v.8h.8M377.1 85.6l-1.6 1.5v-.7v.7h.8"/>
<path d="M377.1 92.3l.3 .7h-.7zM377.6 92.2l-.2 .1h-.7l-.1 .2M379.6 92.7h-1.8v5.1M379.6 90.9h-2.5v3.6h2.5M380.1 92.7h5.3M386.1 99.7v2.5h-1.3l1.3 1.3 1.2-1.3h-1.2M386.1 93.3v1.3M386.7 92.7h1.3M393.1 92.7h1.2M10 110h2M17.1 103.5v2.5M17.1 109.9v2.7"/>
<path d="M17.1 114.7v2.8M17.1 103.5l-.7 1.3M17.1 103.5l.8 1.3M26 109.9v2.7M26 114.7v2.8M43.9 113.7h1.8M45.7 111.1v5.1M47 116.2v3.8h1.3l-1.3 1.3-1.3-1.3h1.3M47 108.6v2.5M57.1 118.7v1.3h1.3l-1.3 1.3-1.2-1.3h1.2M57.1 109.9v2.7M57.1 114.7v2.8"/>
<path d="M78.1 113.7v-1.3l-1.3 1.3 1.3 1.2v-1.2h1.3M81.9 118.7h2.8M81.9 108.6h2.8M88.3 113.7h.2M89.8 111.1h-1.3v5.1h1.3M92.1 115.7v1.8M93.3 118.7h1.3M94.4 111.1h1.2v5.1h-1.2M97.2 113.7h1.2v-1.3l1.3 1.3-1.3 1.2v-1.2M99.7 118.7h1.3M135.6 116.5h.5v1h-.5zM135.9 117.5v2.5"/>
<path d="M138.2 116.5h.5v1h-.5zM138.4 117.5v2.5M147.6 102h1v.5h-1zM147.6 107.1h1v.5h-1zM147.6 104.5h1v.5h-1zM147.6 109.6h1v.5h-1zM148.6 104.8h2.5M148.6 102.2h2.5M148.6 107.3h2.5M148.6 109.9h2.5M165.7 103.5l1.3 .8M165.7 103.5h6.4"/>
<path d="M167 108.6v-1.3l-1.3 1.3 1.3 1.3v-1.3h5.1M167 102.7l-1.3 .8M168.3 106h3.8M172.1 108.5h1.3v.2h-1.3zM172.1 105.9h1.3v.3h-1.3zM172.1 103.4h1.3v.2h-1.3zM175.9 108.5h1.3v.2h-1.3zM175.9 105.9h1.3v.3h-1.3zM175.9 103.4h1.3v.2h-1.3zM177.2 108.6h3.8M177.2 103.5h3.8M177.2 106h3.8"/>
<path d="M309.9 113l1.2 .8M309.9 113h6.3M311.1 106.7v-1.3l-1.2 1.3 1.2 1.3v-1.3h5.1M311.1 112.3l-1.2 .7M312.4 101.6h3.8M312.4 104.1h3.8M312.4 115.6h3.8M312.4 118.1h3.8M316.2 106.6h1.3v.2h-1.3zM316.2 104h1.3v.3h-1.3zM316.2 101.5h1.3v.2h-1.3zM316.2 118h1.3v.2h-1.3z"/>
<path d="M316.2 115.4h1.3v.3h-1.3zM316.2 112.9h1.3v.3h-1.3zM361.3 101v1.2h1.3l-1.3 1.3-1.3-1.3h1.3M361.3 118.1v3.8M361.3 118.1l-.7 1.3M361.3 118.1l.8 1.3M377.8 101v1.2h-1.2l1.2 1.3 1.3-1.3h-1.3M377.8 118.1v3.8M377.8 118.1l.8 1.3M377.8 118.1l-.7 1.3M408 110h2M17.1 120v1.3h1.3l-1.3 1.3-1.2-1.3h1.2"/>
<path d="M29.8 139.1l-.7 1.2M29.8 139.1v2.5M29.8 139.1l.8 1.2M34.9 139.1l-.7 1.2M34.9 139.1v2.5M34.9 139.1l.8 1.2M62.9 137.8l1.2 .8M62.9 137.8h7.1M64.1 137l-1.2 .8M70.5 139.8l-.4 .2-.1 .3 .1 .4 .4 .1M70.5 137.3l-.4 .1-.1 .4 .1 .3 .4 .2M73 139.8l.4 .2 .1 .3-.1 .4-.4 .1"/>
<path d="M73 137.3l.4 .1 .1 .4-.1 .4-.4 .1M73.5 137.8h7.1M79.4 137l1.2 .8M80.6 137.8l-1.2 .8M93.3 137.8h7.2M93.3 137.8l1.3 .8M94.6 137l-1.3 .8M101 139.8l-.4 .2-.1 .3 .1 .4 .4 .1M101 137.3l-.4 .1-.1 .4 .1 .3 .4 .2M103.5 139.8l.4 .2 .1 .3-.2 .4-.3 .1M103.5 137.3l.4 .1 .1 .4-.2 .4-.3 .1M104 137.8h7.1"/>
<path d="M109.9 137l1.2 .8M111.1 137.8l-1.2 .8M123.2 137.8h7.1M123.2 137.8l1.3 .8M124.5 137l-1.3 .8M130.8 139.8l-.3 .2-.2 .3 .1 .4 .4 .1M130.8 137.3l-.3 .1-.2 .4 .1 .3 .4 .2M133.3 139.8l.4 .2 .2 .3-.2 .4-.4 .1M133.3 137.3l.4 .1 .2 .4-.2 .4-.4 .1M133.9 137.8h7.1M137.2 120v1.3h1.2l-1.2 1.3-1.3-1.3h1.3M139.7 137l1.3 .8"/>
<path d="M141 137.8l-1.3 .8M311.1 120.7v-1.3l-1.2 1.3 1.2 1.2v-1.2h5.1M316.2 120.5h1.3v.3h-1.3zM359.5 139.2h2.6v3.5h-2.6M361.3 127v12.2M362.1 135.1l1.5 1.6v-.8v.8h-.8M362.1 133.9l1.5 1.5v-.8v.8h-.8M377.1 135.1l-1.6 1.6v-.8v.8h.8M377.1 133.9l-1.6 1.5v-.8v.8h.8M377.8 127v12.2M379.6 139.2h-2.5v3.5h2.5M10 160h2"/>
<path d="M19 142.9v-1.3l-1.2 1.3 1.2 1.2v-1.2h4.1M22.2 159.4h2.6M22.2 154.3h2.6M27.8 154.3h2v1h1.8M28.1 159.4h1.7v1h1.8M29.8 144.1v2.6M31.6 158.4h-1.8v1M31.6 153.3h-1.8v1M31.6 157.4l1.8 1-1.8 1zM31.6 152.3l1.8 1-1.8 1zM31.6 155.3l1.8-1v2zM33.4 158.4h1.8v1h1.2"/>
<path d="M33.4 153.3h1.8v1h1.2M34.9 144.1v2.6M35.2 159.4v1h-1.8M35.2 154.3v1h-1.8M36.8 142.9h2.8M40 159.4h2.5M40 154.3h2.5M41.7 142.9h4v-1.3l1.3 1.3-1.3 1.2v-1.2M51.4 140.3h1.3M57.8 140.3h1.3M62.9 158.8h7.1M62.9 158.8l1.2 .7"/>
<path d="M62.9 148.6h7.1M62.9 148.6l1.2 .8M64.1 142.9v-1.3l-1.2 1.3 1.2 1.2v-1.2h5.9M64.1 153.7v-1.3l-1.2 1.3 1.2 1.2v-1.2h5.9M64.1 158l-1.2 .8M64.1 147.8l-1.2 .8M65.4 151.1h4.6M65.4 140.3h4.6M70.5 153.2l-.4 .1-.1 .4 .1 .3 .4 .2M70.5 150.6l-.4 .2-.1 .3 .1 .4 .4 .1M70.5 148.1l-.4 .1-.1 .4 .1 .3 .4 .2M70.5 142.4l-.4 .1-.1 .4 .1 .3 .4 .2"/>
<path d="M70.5 158.2l-.4 .2-.1 .3 .1 .4 .4 .2M73 153.2l.4 .1 .1 .4-.1 .3-.4 .2M73 150.6l.4 .2 .1 .3-.1 .4-.4 .1M73 148.1l.4 .1 .1 .4-.1 .4-.4 .1M73 142.4l.4 .1 .1 .4-.1 .3-.4 .2M73 158.2l.4 .2 .1 .4-.1 .3-.4 .2M73.5 153.7h5.9v-1.3l1.2 1.3-1.2 1.2v-1.2M73.5 142.9h5.9v-1.3l1.2 1.3-1.2 1.2v-1.2M73.5 158.8h7.1M73.5 151.1h4.6M73.5 148.6h7.1M73.5 140.3h4.6"/>
<path d="M79.4 158l1.2 .8M79.4 147.8l1.2 .8M80.6 158.8l-1.2 .7M80.6 148.6l-1.2 .8M93.3 158.8h7.2M93.3 148.6h7.2M93.3 148.6l1.3 .8M93.3 158.8l1.3 .7M94.6 142.9v-1.3l-1.3 1.3 1.3 1.2v-1.2h5.9M94.6 153.7v-1.3l-1.3 1.3 1.3 1.2v-1.2h5.9M94.6 147.8l-1.3 .8M94.6 158l-1.3 .8"/>
<path d="M95.9 151.1h4.6M95.9 140.3h4.6M101 153.2l-.4 .1-.1 .4 .1 .3 .4 .2M101 150.6l-.4 .2-.1 .3 .1 .4 .4 .1M101 148.1l-.4 .1-.1 .4 .1 .3 .4 .2M101 142.4l-.4 .1-.1 .4 .1 .3 .4 .2M101 158.2l-.4 .2-.1 .3 .1 .4 .4 .2M103.5 153.2l.4 .1 .1 .4-.2 .3-.3 .2M103.5 150.6l.4 .2 .1 .3-.2 .4-.3 .1M103.5 148.1l.4 .1 .1 .4-.2 .4-.3 .1M103.5 142.4l.4 .1 .1 .4-.2 .3-.3 .2M103.5 158.2l.4 .2 .1 .4-.2 .3-.3 .2"/>
<path d="M104 153.7h5.9v-1.3l1.2 1.3-1.2 1.2v-1.2M104 142.9h5.9v-1.3l1.2 1.3-1.2 1.2v-1.2M104 158.8h7.1M104 151.1h4.6M104 148.6h7.1M104 140.3h4.6M109.9 147.8l1.2 .8M109.9 158l1.2 .8M111.1 148.6l-1.2 .8M111.1 158.8l-1.2 .7M123.2 158.8h7.1M123.2 148.6h7.1"/>
<path d="M123.2 158.8l1.3 .7M123.2 148.6l1.3 .8M124.5 142.9v-1.3l-1.3 1.3 1.3 1.2v-1.2h5.8M124.5 153.7v-1.3l-1.3 1.3 1.3 1.2v-1.2h5.8M124.5 158l-1.3 .8M124.5 147.8l-1.3 .8M125.7 151.1h4.6M125.7 140.3h4.6M130.8 158.2l-.3 .2-.2 .3 .1 .4 .4 .2M130.8 153.2l-.3 .1-.2 .4 .1 .3 .4 .2M130.8 150.6l-.3 .2-.2 .3 .1 .4 .4 .1M130.8 148.1l-.3 .1-.2 .4 .1 .3 .4 .2"/>
<path d="M130.8 142.4l-.3 .1-.2 .4 .1 .3 .4 .2M133.3 142.4l.4 .1 .2 .4-.2 .3-.4 .2M133.3 158.2l.4 .2 .2 .4-.2 .3-.4 .2M133.3 153.2l.4 .1 .2 .4-.2 .3-.4 .2M133.3 150.6l.4 .2 .2 .3-.2 .4-.4 .1M133.3 148.1l.4 .1 .2 .4-.2 .4-.4 .1M133.9 153.7h5.8v-1.3l1.3 1.3-1.3 1.2v-1.2M133.9 142.9h5.8v-1.3l1.3 1.3-1.3 1.2v-1.2M133.9 158.8h7.1M133.9 151.1h4.5M133.9 148.6h7.1M133.9 140.3h4.5"/>
<path d="M139.7 158l1.3 .8M139.7 147.8l1.3 .8M141 158.8l-1.3 .7M141 148.6l-1.3 .8M151.1 140.3h1.3M157.5 140.3h1.2M344.8 141h1.3M351.2 141h1.2M353.1 148v2.5h1.2l-1.2 1.3-1.3-1.3h1.3M353.1 141.6v1.3M353.7 141h5.3M359.5 141h1.8v5.1"/>
<path d="M361.3 149.2v1.3h1.3l-1.3 1.3-1.3-1.3h1.3M361.6 140.5l.1 .1h.8l.1 .1M362.1 140.6l.4 .6h-.8zM377.1 140.6l.3 .6h-.7zM377.6 140.5l-.2 .1h-.7l-.1 .1M377.8 149.2v1.3h-1.2l1.2 1.3 1.3-1.3h-1.3M379.6 141h-1.8v5.1M380.1 141h5.3M386.1 148v2.5h-1.3l1.3 1.3 1.2-1.3h-1.2M386.1 141.6v1.3M386.7 141h1.3M393.1 141h1.2"/>
<path d="M408 160h2M15.9 164.5l1.2 .7M15.9 164.5h2.5M17.1 163.7l-1.2 .8M20.3 172.7v2.6h1.3l-1.3 1.2-1.3-1.2h1.3M20.3 166.4v1.2M22.2 164.5h2.6M31.6 160.4l1.8-1v2zM32.4 167v3.8h1.3l-1.3 1.3-1.3-1.3h1.3M64.1 163.8v-1.2l-1.2 1.2 1.2 1.3v-1.3h5.9M65.4 161.3h4.6M70.5 163.3l-.4 .2-.1 .3 .1 .4 .4 .1"/>
<path d="M70.5 160.8l-.4 .1-.1 .4 .1 .3 .4 .2M73 163.3l.4 .2 .1 .3-.1 .4-.4 .1M73 160.8l.4 .1 .1 .4-.1 .4-.4 .1M73.5 163.8h5.9v-1.2l1.2 1.2-1.2 1.3v-1.3M73.5 161.3h4.6M94.6 163.8v-1.2l-1.3 1.2 1.3 1.3v-1.3h5.9M95.9 161.3h4.6M101 163.3l-.4 .2-.1 .3 .1 .4 .4 .1M101 160.8l-.4 .1-.1 .4 .1 .3 .4 .2M103.5 163.3l.4 .2 .1 .3-.2 .4-.3 .1M103.5 160.8l.4 .1 .1 .4-.2 .4-.3 .1M104 163.8h5.9v-1.2l1.2 1.2-1.2 1.3v-1.3"/>
<path d="M104 161.3h4.6M124.5 163.8v-1.2l-1.3 1.2 1.3 1.3v-1.3h5.8M125.7 161.3h4.6M130.8 163.3l-.3 .2-.2 .3 .1 .4 .4 .1M130.8 160.8l-.3 .1-.2 .4 .1 .3 .4 .2M133.3 163.3l.4 .2 .2 .3-.2 .4-.4 .1M133.3 160.8l.4 .1 .2 .4-.2 .4-.4 .1M133.9 163.8h5.8v-1.2l1.3 1.2-1.3 1.3v-1.3M133.9 161.3h4.5M10 210h2M408 210h2M10 260h2"/>
<path d="M300 253h108v32h-108zM408 260h2M300 278.5h108M300 274.5h108M300 268.5h108M305.5 273.2v.2M305.5 272.5v.1M307.7 270.5v.2M307.7 269.8v.1M310.6 269.1l-1.3 1.9M320 278.5v3M322.7 273.1l.2 .3 .5-.1"/>
<path d="M323.4 272.5l-.5-.1-.2 .3M324 272.5l.2-.1 .4 .1 .1 .9M324 271.9v1.5M384 278.5v6.5M60 285v2M110 285v2M160 285v2M210 285v2M260 285v2M300 281.5h108M310 285v2M360 285v2"/>
<path d="M393.3 283.6h.9M393.3 282.5l.4-.4v1.5"/>
<circle cx="47" cy="115.7" r=".51"/>
<circle cx="47" cy="111.6" r=".51"/>
</g>
<g fill="none" stroke="#840000" stroke-width=".25">
<path d="M36.2 32.4h40.6v45.7h-40.6zM249.2 34.9h2v5.1h-2zM316.2 25.4h2.6v10.2h-2.6zM360 34.3h2.6l-1.3 2.5zM360 36.8h2.6M360.3 25.4h2v5.1h-2zM376.6 34.3h2.5l-1.3 2.5zM376.6 36.8h2.5M376.8 25.4h2v5.1h-2zM249.2 43.8h2v5.1h-2zM316.2 40h2.6v10.2h-2.6zM346.1 43.4h5.1v2.1h-5.1z"/>
<path d="M352 46.4h2.1v5h-2.1zM359 42.5v3.9M359.5 42.2v1M359.5 43.9v1.1M359.5 45.7v1M379.6 42.2v1M379.6 43.9v1.1M379.6 45.7v1M380.1 42.5v3.9M385.1 46.4h2v5h-2zM388 43.4h5.1v2.1h-5.1zM252.1 65.4h10.2v7h-10.2z"/>
<path d="M316.2 61.6h2.6v10.2h-2.6zM316.2 76.2h2.6v10.2h-2.6zM360.3 73.7h2v5h-2zM376.8 73.7h2v5h-2zM128.3 92.1h20.3v25.4h-20.3zM316.2 97.8h2.6v10.2h-2.6zM346.1 91.7h5.1v2h-5.1zM352 94.6h2.1v5.1h-2.1zM359 90.8v3.8M359.5 90.4v1M359.5 92.2v1M359.5 94v1"/>
<path d="M360 82.6h2.6l-1.3 2.5zM360 85.1h2.6M376.6 82.6h2.5l-1.3 2.5zM376.6 85.1h2.5M379.6 90.4v1M379.6 92.2v1M379.6 94v1M380.1 90.8v3.8M385.1 94.6h2v5.1h-2zM388 91.7h5.1v2h-5.1zM94.6 117.7h5.1v2.1h-5.1zM172.1 102.2h5.1v7.7h-5.1z"/>
<path d="M316.2 111.8h2.6v10.1h-2.6zM52.7 139.3h5.1v2.1h-5.1zM152.4 139.3h5.1v2.1h-5.1zM346.1 140h5.1v2h-5.1zM359 139.1v3.8M359.5 138.7v1M360 130.8h2.6l-1.3 2.6zM360 133.4h2.6M360.3 121.9h2v5.1h-2zM376.6 130.8h2.5l-1.3 2.6zM376.6 133.4h2.5M376.8 121.9h2v5.1h-2z"/>
<path d="M379.6 138.7v1M380.1 139.1v3.8M388 140h5.1v2h-5.1zM24.8 146.7h15.2v20.3h-15.2zM352 142.9h2.1v5.1h-2.1zM359.5 140.5v1M359.5 142.2v1.1M379.6 140.5v1M379.6 142.2v1.1M385.1 142.9h2v5.1h-2zM19.3 167.6h2v5.1h-2z"/>
<circle cx="360.4" cy="44.4" r="2.79"/>
<circle cx="378.7" cy="44.4" r="2.79"/>
<circle cx="360.4" cy="92.7" r="2.79"/>
<circle cx="378.7" cy="92.7" r="2.79"/>
<circle cx="360.4" cy="141" r="2.79"/>
<circle cx="378.7" cy="141" r="2.79"/>
</g>
<g fill="none" stroke="#006464" stroke-width=".18">
<path d="M243.1 18.4h.5l.2 .2-.1 .4h-.6M243.4 19l.4 .6M316.6 17.1h.6M360.6 16.5l1.3 .4M377.1 16.5l1.3 .4M63.6 33.4a.68 .68 0 0 1 1.1 .3 .72 .72 0 0 1-1.3-.2zM218.5 31.1h.6M226.8 31.1h.6M256.2 38.8l.4 .5M256.6 38.5l-.5 .5M279.4 30.4l-.4 1.3M331 31.1a.8 .8 0 0 1 0 1.2"/>
<path d="M45.7 59.6l.4 1.3M50.8 52v1.3M52.2 52v1.3l-.8-1.3v1.3M52.9 54.6v1l-.1 .2M53.3 54.6h.7M53.7 54.6v1.2M75.1 52.3v.7M75.6 54.4h.3v1.8h-.3M75.6 51.9h.3v1.8h-.3M316.6 53.3h.6M329.2 45.7a.68 .68 0 0 1 .4 .6 .68 .68 0 0 1-.4 .6M83 80h-.3"/>
<path d="M240.5 66.6l-.5 1.3M246.8 74.2h.6M261.8 62.8h.8l-.4 .5 .3 .1 .1 .4-.3 .3h-.3M263.1 63.4h.5M263.7 62.8h-.6v1.3h.6M271.2 74.2h.7M278.4 66.6h.8l-.4 .5M279 67.1l.2 .2v.3l-.2 .3M329.3 68.1h.8M329.9 67.7v.8M360.6 64.8l1.3 .4M377.1 64.8l1.3 .4"/>
<path d="M82.7 80.4l.3 .1 .2 .2-.1 .4-.4 .1M139.9 85h.8l-.4 .5M140.5 85.5l.2 .3v.3l-.2 .2M141.9 96.1h5.4M317.3 90.1h.6M328.9 82.7h.7M329.5 82.3v.8M18.7 101.5h.7l-.4 .5M19.2 102l.2 .3v.3l-.2 .2M23.6 115.5h.6M62.3 115.5h.6M106 109.1l-.3 .9h.7"/>
<path d="M106.3 109.6v.8M135.6 106.6v.5M136.5 106.6l-.1 .3M147.2 109.2v1.2M164.1 102.8h.8l-.5 .5M164.6 103.3l.3 .2v.3M183.9 100.1h-.3M329.1 117.4l.4 .1 .1 .2-.3 .3M329.1 118h.2M329.3 118l.3 .2v.2l-.1 .2-.4 .1M329.5 103.4h.3l.2 .3-.2 .3M329.5 104h.3"/>
<path d="M329.8 104l.2 .2v.3l-.2 .2h-.3M360.6 113l1.3 .4M377.1 113l1.3 .4M22.3 139.6h.6M31.4 136.5h.7l-.4 .5M31.9 137l.2 .2v.3l-.2 .2M34.2 135.2l1.3 .5M46.1 139.6h.6M62 137.1l-.4 1.3M85.7 137.1l-.4 1.3M92.5 137.1l-.4 1.3M105.6 135.2h.8"/>
<path d="M116.2 137.1l-.4 1.3M122.4 137.1l-.5 1.3M146.1 137.1l-.5 1.3M64.6 156.2l-.4 1.2M64.6 146l-.4 1.3M75.2 156.2h.7M81.9 156.2l-.4 1.2M82.6 146l-.5 1.3M95.1 146l-.5 1.3M95.1 156.2l-.5 1.2M112.4 156.2l-.4 1.2M113 146l-.4 1.3"/>
<path d="M124.9 156.2l-.4 1.2M124.9 146l-.4 1.3M142.3 156.2l-.5 1.2M142.9 146l-.4 1.3M16.7 161.9h.8l-.5 .5M17.2 162.4l.3 .2v.3l-.3 .2M46.3 170.8v1l-.3 .2"/>
</g>
<g fill="#840000" stroke="#840000" stroke-width=".18">
<path d="M378.3 140.6l1 .4-1 .4z"/>
<path d="M359.8 141l1-.4v.8z"/>
<path d="M378.3 92.3l1 .4-1 .4z"/>
<path d="M359.8 92.7l1-.4v.8z"/>
<path d="M359.8 44.5l1-.4v.7z"/>
<path d="M378.3 44.1l1 .4-1 .3z"/>
<circle cx="377.8" cy="142.7" r=".25"/>
<circle cx="377.8" cy="139.2" r=".25"/>
<circle cx="361.3" cy="142.7" r=".25"/>
<circle cx="361.3" cy="139.2" r=".25"/>
<circle cx="377.8" cy="94.5" r=".25"/>
<circle cx="377.8" cy="90.9" r=".25"/>
<circle cx="361.3" cy="94.5" r=".25"/>
<circle cx="361.3" cy="90.9" r=".25"/>
<circle cx="361.3" cy="46.2" r=".25"/>
<circle cx="361.3" cy="42.7" r=".25"/>
<circle cx="377.8" cy="46.2" r=".25"/>
<circle cx="377.8" cy="42.7" r=".25"/>
</g>
<g fill="#ffffc2" stroke="#ffffc2" stroke-width=".18">
<path d="M316.2 61.6h2.6v10.2h-2.6z"/>
<path d="M316.2 97.8h2.6v10.2h-2.6z"/>
<path d="M316.2 76.2h2.6v10.2h-2.6z"/>
<path d="M316.2 111.8h2.6v10.1h-2.6z"/>
<path d="M128.3 92.1h20.3v25.4h-20.3z"/>
<path d="M172.1 102.2h5.1v7.7h-5.1z"/>
<path d="M316.2 40h2.6v10.2h-2.6z"/>
<path d="M316.2 25.4h2.6v10.2h-2.6z"/>
<path d="M24.8 146.7h15.2v20.3h-15.2z"/>
<path d="M228.6 21.6h15.2v26.7h-15.2z"/>
<path d="M36.2 32.4h40.6v45.7h-40.6z"/>
<path d="M252.1 65.4h10.2v7h-10.2z"/>
</g>
<g fill="none" stroke="#840000" stroke-width=".51">
<path d="M312.3 19.6v4M314.3 19.6a3.3 3.3 0 0 0 0 4M211.3 30h4.1M211.3 28.4h4.1M218.9 30h4.1M218.9 28.4h4.1M259 38.2h4M259 36.7h4M265.3 38.2h4.1M265.3 36.7h4.1M271.7 38.2h4M271.7 36.7h4"/>
<path d="M221.5 47.1h4.1M221.5 45.6h4.1M312.3 55.8v4M314.3 55.8a3.3 3.3 0 0 0 0 4M246.3 73.2h4M246.3 71.6h4M264 73.2h4.1M264 71.6h4.1M312.3 91.9v4.1M314.3 91.9a3.3 3.3 0 0 0 0 4.1M15.1 114.4h4.1M15.1 112.9h4.1"/>
<path d="M24 114.4h4.1M24 112.9h4.1M55.1 114.4h4.1M55.1 112.9h4.1M85 106.6v4M85 116.7v4.1M86.5 106.6v4M86.5 116.7v4.1M90.8 115.7h2.5M90.8 111.6h2.5M23.4 140.8v4.1M24.9 140.8v4.1"/>
<path d="M39.9 140.8v4.1M41.4 140.8v4.1"/>
</g>
<path d="M89.5 112.5h5.1v2.3h-5.1z" fill="none" stroke="#840000" stroke-width=".3"/>
<path d="M48.5 28.9v.7M79.6 57.4h.7M227.6 44h.7M51 79.7v.7" fill="none" stroke="#a90000" stroke-width=".18"/>
<g fill="none" stroke="#840000" stroke-width="1.3">
<circle cx="243.8" cy="95.2" r="1.27"/>
<circle cx="252.7" cy="95.2" r="1.27"/>
<circle cx="262.3" cy="95.2" r="1.27"/>
</g>
<g fill="none" stroke="#0000c2" stroke-width=".18">
<path d="M202.6 13.3h77.4v43.2h-77.4zM207 14.2l-.4 1.3M222.1 14.6l-.4 .3M280.7 13.3h52v115h-52zM333.4 13.3h73v47.7h-73zM234.9 57.2h45.1v25.4h-45.1zM238.8 58l-.4 1.3M257.7 58.4l-.3 .1M333.4 61.6h73v47.6h-73zM13.3 99.7h29.2v26.7h-29.2zM43.2 99.7h29.2v26.7h-29.2zM73 99.7h40.7v26.7h-40.7z"/>
<path d="M114.3 83.2h75.6v43.2h-75.6zM129.6 84.5v.8M130 84.5l-.4 .2M234.9 83.2h45.1v24.8h-45.1zM242.7 85.2l.2 .1h.4M243.3 84.5h-.4l-.2 .1M243.3 84.5v1l-.3 .2h-.3M40.4 101v.8M40.4 101.1l.2-.1h.3l.1 .8M99 100.6v1l.2 .2M99.6 100.4a1.46 1.46 0 0 1 0 1.9M333.4 109.9h73v47.6h-73z"/>
<path d="M13.3 127h151.8v56.5h-151.8zM158.5 134l.2 .2v.6M158.7 134.8h-.4M158.7 134.3l-.4 .1M159.3 133.6v1.1l.2 .1"/>
</g>
<path d="M150.5 135.9h9.5v8.9h-9.5v-8.9" fill="none" stroke="#0000c2" stroke-width=".18" stroke-dasharray="1.7 .6"/>
<g fill="none" stroke="#009600" stroke-width=".18">
<path d="M212.7 22.9h13.4M213.4 22.9v2.5M221 22.9v2.5M225.4 22.9v2.5h.7M246.4 22.9h1.2v2.5h-1.2M246.4 33h29.2M250.2 33v.7M261 33v.7M267.3 33v.7M273.7 33v.7M295.9 31.8h16.5M295.9 29.2h16.5"/>
<path d="M302.3 31.8v14.6h10.1M304.2 29.2v14.6h8.2M307.3 21.6h1.3v5.1M307.3 26.7h5.1M312.4 34.3v1.3M225.4 41.9v2.6h.7M226.1 41.9h-2.6v.6M246.4 41.9h3.8M250.2 41.3v1.2M261 41.3v.6h12.7v-.6M267.3 41.3v1.2M308.6 57.8v5.1"/>
<path d="M352.4 44.5h1.3M353.1 44.5v.6M361.3 49.5v3.2M377.8 49.5v3.2M385.4 44.5h1.3M386.1 44.5v.6M244.5 67.3h5.1M248.3 67.3v1.3M257.2 74.9v1.3M264.8 67.3h5.7M266.1 67.3v1.3M297.2 65.4h15.2"/>
<path d="M297.2 67.9h15.2M302.3 67.9v14.7h10.1M304.2 65.4v14.6h8.2M307.3 62.9h5.1M243.8 99.1h25.4M307.3 99.1h5.1M308.6 94v5.1M352.4 92.7h1.3M353.1 92.7v.6M361.3 97.8v3.2M377.8 97.8v3.2M385.4 92.7h1.3"/>
<path d="M386.1 92.7v.6M17.1 108.6h15.3M17.1 118.7h15.3M17.1 106v3.9M17.1 117.5v2.5M26 108.6v1.3M26 117.5v1.2M47 108.6h19M57.1 108.6v1.3M57.1 117.5v1.2M79.4 113.7h7.6M80.6 108.6v10.1"/>
<path d="M89.5 108.6h12.7M89.5 118.7h3.8M92.1 108.6v1.3M92.1 117.5v1.2M101 118.7h1.2M297.2 101.6h15.2M297.2 104.1h15.2M302.3 104.1v14h10.1M304.2 101.6v14h8.2M135.9 120h2.5M27.9 142.9h1.9M29.8 141.6v2.5"/>
<path d="M34.9 142.9h1.9M34.9 141.6v2.5M51.4 140.3h-.6v14h-8.3M59.1 140.3h6.3M60.3 140.3v21h5.1M60.3 151.1h5.1M78.1 140.3h17.8M78.1 151.1h7.6M85.7 140.3v21h-7.6M88.3 151.1h7.6M88.3 140.3v21h7.6M108.6 140.3h17.1"/>
<path d="M108.6 151.1h7.6M116.2 140.3v21h-7.6M118.1 151.1h7.6M118.1 140.3v21h7.6M138.4 140.3h12.7M138.4 151.1h7.6M146 140.3v21h-7.6M158.7 140.3h4.5v33.1h-112.4v-14h-8.3M352.4 141h1.3M353.1 141v.6M361.3 146.1v3.1M377.8 146.1v3.1"/>
<path d="M385.4 141h1.3M386.1 141v.6M18.4 164.5h3.8M20.3 164.5v1.9"/>
</g>
<g fill="none" stroke="#000084" stroke-width=".18">
<path d="M45.7 26.7l1.3 1.2M47 26.7l-1.3 1.2M48.3 26.7l1.2 1.2M49.5 26.7l-1.2 1.2M50.8 26.7l1.2 1.2M52 26.7l-1.2 1.2M53.4 26.7l1.2 1.2M54.6 26.7l-1.2 1.2M55.9 26.7l1.2 1.2M57.1 26.7l-1.2 1.2M58.4 26.7l1.3 1.2M59.7 26.7l-1.3 1.2"/>
<path d="M61 26.7l1.2 1.2M62.2 26.7l-1.2 1.2M225.5 38.8l1.2 1.2M226.7 38.8l-1.2 1.2M245.8 27.3l1.2 1.2M247 27.3l-1.2 1.2M81.3 52.1l1.2 1.2M81.3 54.6l1.2 1.3M81.3 59.7l1.2 1.2M82.5 52.1l-1.2 1.2M82.5 54.6l-1.2 1.3M82.5 59.7l-1.2 1.2"/>
<path d="M45.7 82.6l1.3 1.2M47 82.6l-1.3 1.2M48.3 82.6l1.2 1.2M49.5 82.6l-1.2 1.2M50.8 82.6l1.2 1.2M52 82.6l-1.2 1.2M55.9 82.6l1.2 1.2M57.1 82.6l-1.2 1.2M58.4 82.6l1.3 1.2M59.7 82.6l-1.3 1.2M61 82.6l1.2 1.2M62.2 82.6l-1.2 1.2"/>
<path d="M63.5 82.6l1.2 1.2M64.7 82.6l-1.2 1.2M150.5 106.7l1.2 1.2M150.5 109.2l1.2 1.3M151.7 106.7l-1.2 1.2M151.7 109.2l-1.2 1.3M180.4 108l1.2 1.2M181.6 108l-1.2 1.2"/>
</g>
<g fill="#009600" stroke="#009600" stroke-width=".18">
<circle cx="221" cy="22.9" r=".46"/>
<circle cx="225.4" cy="41.9" r=".46"/>
<circle cx="225.4" cy="22.9" r=".46"/>
<circle cx="213.4" cy="22.9" r=".46"/>
<circle cx="252.7" cy="99.1" r=".46"/>
<circle cx="262.3" cy="99.1" r=".46"/>
<circle cx="273.7" cy="33" r=".46"/>
<circle cx="248.3" cy="67.3" r=".46"/>
<circle cx="266.1" cy="67.3" r=".46"/>
<circle cx="304.2" cy="65.4" r=".46"/>
<circle cx="302.3" cy="67.9" r=".46"/>
<circle cx="308.6" cy="62.9" r=".46"/>
<circle cx="304.2" cy="29.2" r=".46"/>
<circle cx="302.3" cy="31.8" r=".46"/>
<circle cx="308.6" cy="21.6" r=".46"/>
<circle cx="250.2" cy="41.9" r=".46"/>
<circle cx="250.2" cy="33" r=".46"/>
<circle cx="267.3" cy="33" r=".46"/>
<circle cx="261" cy="33" r=".46"/>
<circle cx="267.3" cy="41.9" r=".46"/>
<circle cx="92.1" cy="108.6" r=".46"/>
<circle cx="60.3" cy="151.1" r=".46"/>
<circle cx="57.1" cy="108.6" r=".46"/>
<circle cx="60.3" cy="140.3" r=".46"/>
<circle cx="85.7" cy="140.3" r=".46"/>
<circle cx="88.3" cy="140.3" r=".46"/>
<circle cx="85.7" cy="151.1" r=".46"/>
<circle cx="88.3" cy="151.1" r=".46"/>
<circle cx="26" cy="118.7" r=".46"/>
<circle cx="26" cy="108.6" r=".46"/>
<circle cx="17.1" cy="118.7" r=".46"/>
<circle cx="17.1" cy="108.6" r=".46"/>
<circle cx="92.1" cy="118.7" r=".46"/>
<circle cx="80.6" cy="113.7" r=".46"/>
<circle cx="386.1" cy="92.7" r=".46"/>
<circle cx="353.1" cy="92.7" r=".46"/>
<circle cx="304.2" cy="101.6" r=".46"/>
<circle cx="302.3" cy="104.1" r=".46"/>
<circle cx="308.6" cy="99.1" r=".46"/>
<circle cx="353.1" cy="141" r=".46"/>
<circle cx="386.1" cy="141" r=".46"/>
<circle cx="386.1" cy="44.5" r=".46"/>
<circle cx="353.1" cy="44.5" r=".46"/>
<circle cx="308.6" cy="26.7" r=".46"/>
<circle cx="312.4" cy="34.3" r=".46"/>
<circle cx="29.8" cy="142.9" r=".46"/>
<circle cx="34.9" cy="142.9" r=".46"/>
<circle cx="20.3" cy="164.5" r=".46"/>
<circle cx="137.2" cy="120" r=".46"/>
<circle cx="146" cy="151.1" r=".46"/>
<circle cx="146" cy="140.3" r=".46"/>
<circle cx="118.1" cy="151.1" r=".46"/>
<circle cx="116.2" cy="151.1" r=".46"/>
<circle cx="116.2" cy="140.3" r=".46"/>
<circle cx="118.1" cy="140.3" r=".46"/>
</g>
<use href="#words"/>
</svg>
